VERSION 5.7 ;
  NOWIREEXTENSIONATPIN ON ;
  DIVIDERCHAR "/" ;
  BUSBITCHARS "[]" ;
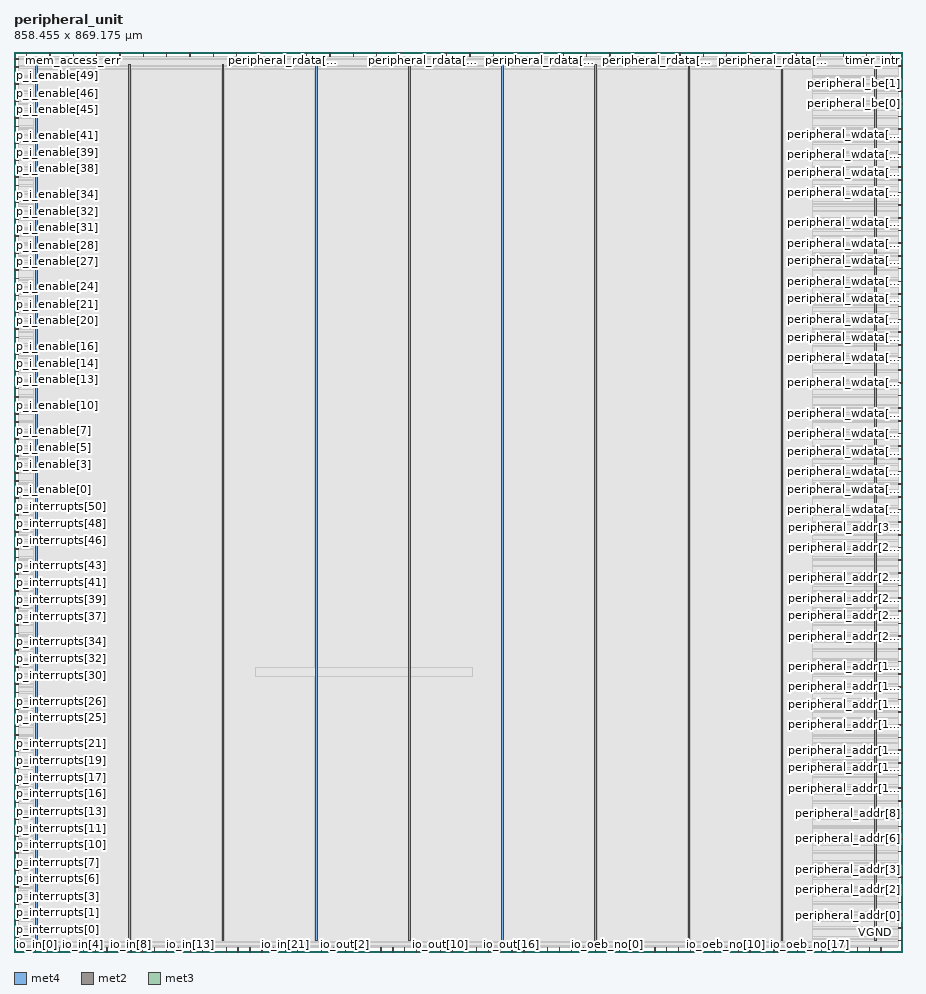
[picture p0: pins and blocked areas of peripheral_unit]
MACRO peripheral_unit
  CLASS BLOCK ;
  FOREIGN peripheral_unit ;
  ORIGIN 0.000 0.000 ;
  SIZE 858.455 BY 869.175 ;
  PIN VGND
    USE GROUND ;
    PORT
      LAYER met4 ;
        RECT 831.040 10.640 832.640 857.040 ;
    END
    PORT
      LAYER met4 ;
        RECT 651.040 10.640 652.640 857.040 ;
    END
    PORT
      LAYER met4 ;
        RECT 471.040 10.640 472.640 857.040 ;
    END
    PORT
      LAYER met4 ;
        RECT 291.040 10.640 292.640 857.040 ;
    END
    PORT
      LAYER met4 ;
        RECT 111.040 10.640 112.640 857.040 ;
    END
  END VGND
  PIN VPWR
    USE POWER ;
    PORT
      LAYER met4 ;
        RECT 741.040 10.640 742.640 857.040 ;
    END
    PORT
      LAYER met4 ;
        RECT 561.040 10.640 562.640 857.040 ;
    END
    PORT
      LAYER met4 ;
        RECT 381.040 10.640 382.640 857.040 ;
    END
    PORT
      LAYER met4 ;
        RECT 201.040 10.640 202.640 857.040 ;
    END
    PORT
      LAYER met4 ;
        RECT 21.040 10.640 22.640 857.040 ;
    END
  END VPWR
  PIN clk
    PORT
      LAYER met2 ;
        RECT 12.050 865.175 12.330 869.175 ;
    END
  END clk
  PIN io_in[0]
    PORT
      LAYER met2 ;
        RECT 20.790 0.000 21.070 4.000 ;
    END
  END io_in[0]
  PIN io_in[10]
    PORT
      LAYER met2 ;
        RECT 135.790 0.000 136.070 4.000 ;
    END
  END io_in[10]
  PIN io_in[11]
    PORT
      LAYER met2 ;
        RECT 147.290 0.000 147.570 4.000 ;
    END
  END io_in[11]
  PIN io_in[12]
    PORT
      LAYER met2 ;
        RECT 158.790 0.000 159.070 4.000 ;
    END
  END io_in[12]
  PIN io_in[13]
    PORT
      LAYER met2 ;
        RECT 170.290 0.000 170.570 4.000 ;
    END
  END io_in[13]
  PIN io_in[14]
    PORT
      LAYER met2 ;
        RECT 181.790 0.000 182.070 4.000 ;
    END
  END io_in[14]
  PIN io_in[15]
    PORT
      LAYER met2 ;
        RECT 193.290 0.000 193.570 4.000 ;
    END
  END io_in[15]
  PIN io_in[16]
    PORT
      LAYER met2 ;
        RECT 204.790 0.000 205.070 4.000 ;
    END
  END io_in[16]
  PIN io_in[17]
    PORT
      LAYER met2 ;
        RECT 216.290 0.000 216.570 4.000 ;
    END
  END io_in[17]
  PIN io_in[18]
    PORT
      LAYER met2 ;
        RECT 227.790 0.000 228.070 4.000 ;
    END
  END io_in[18]
  PIN io_in[19]
    PORT
      LAYER met2 ;
        RECT 239.290 0.000 239.570 4.000 ;
    END
  END io_in[19]
  PIN io_in[1]
    PORT
      LAYER met2 ;
        RECT 32.290 0.000 32.570 4.000 ;
    END
  END io_in[1]
  PIN io_in[20]
    PORT
      LAYER met2 ;
        RECT 250.790 0.000 251.070 4.000 ;
    END
  END io_in[20]
  PIN io_in[21]
    PORT
      LAYER met2 ;
        RECT 262.290 0.000 262.570 4.000 ;
    END
  END io_in[21]
  PIN io_in[22]
    PORT
      LAYER met2 ;
        RECT 273.790 0.000 274.070 4.000 ;
    END
  END io_in[22]
  PIN io_in[23]
    PORT
      LAYER met2 ;
        RECT 285.290 0.000 285.570 4.000 ;
    END
  END io_in[23]
  PIN io_in[2]
    PORT
      LAYER met2 ;
        RECT 43.790 0.000 44.070 4.000 ;
    END
  END io_in[2]
  PIN io_in[3]
    PORT
      LAYER met2 ;
        RECT 55.290 0.000 55.570 4.000 ;
    END
  END io_in[3]
  PIN io_in[4]
    PORT
      LAYER met2 ;
        RECT 66.790 0.000 67.070 4.000 ;
    END
  END io_in[4]
  PIN io_in[5]
    PORT
      LAYER met2 ;
        RECT 78.290 0.000 78.570 4.000 ;
    END
  END io_in[5]
  PIN io_in[6]
    PORT
      LAYER met2 ;
        RECT 89.790 0.000 90.070 4.000 ;
    END
  END io_in[6]
  PIN io_in[7]
    PORT
      LAYER met2 ;
        RECT 101.290 0.000 101.570 4.000 ;
    END
  END io_in[7]
  PIN io_in[8]
    PORT
      LAYER met2 ;
        RECT 112.790 0.000 113.070 4.000 ;
    END
  END io_in[8]
  PIN io_in[9]
    PORT
      LAYER met2 ;
        RECT 124.290 0.000 124.570 4.000 ;
    END
  END io_in[9]
  PIN io_oeb_no[0]
    PORT
      LAYER met2 ;
        RECT 572.790 0.000 573.070 4.000 ;
    END
  END io_oeb_no[0]
  PIN io_oeb_no[10]
    PORT
      LAYER met2 ;
        RECT 687.790 0.000 688.070 4.000 ;
    END
  END io_oeb_no[10]
  PIN io_oeb_no[11]
    PORT
      LAYER met2 ;
        RECT 699.290 0.000 699.570 4.000 ;
    END
  END io_oeb_no[11]
  PIN io_oeb_no[12]
    PORT
      LAYER met2 ;
        RECT 710.790 0.000 711.070 4.000 ;
    END
  END io_oeb_no[12]
  PIN io_oeb_no[13]
    PORT
      LAYER met2 ;
        RECT 722.290 0.000 722.570 4.000 ;
    END
  END io_oeb_no[13]
  PIN io_oeb_no[14]
    PORT
      LAYER met2 ;
        RECT 733.790 0.000 734.070 4.000 ;
    END
  END io_oeb_no[14]
  PIN io_oeb_no[15]
    PORT
      LAYER met2 ;
        RECT 745.290 0.000 745.570 4.000 ;
    END
  END io_oeb_no[15]
  PIN io_oeb_no[16]
    PORT
      LAYER met2 ;
        RECT 756.790 0.000 757.070 4.000 ;
    END
  END io_oeb_no[16]
  PIN io_oeb_no[17]
    PORT
      LAYER met2 ;
        RECT 768.290 0.000 768.570 4.000 ;
    END
  END io_oeb_no[17]
  PIN io_oeb_no[18]
    PORT
      LAYER met2 ;
        RECT 779.790 0.000 780.070 4.000 ;
    END
  END io_oeb_no[18]
  PIN io_oeb_no[19]
    PORT
      LAYER met2 ;
        RECT 791.290 0.000 791.570 4.000 ;
    END
  END io_oeb_no[19]
  PIN io_oeb_no[1]
    PORT
      LAYER met2 ;
        RECT 584.290 0.000 584.570 4.000 ;
    END
  END io_oeb_no[1]
  PIN io_oeb_no[20]
    PORT
      LAYER met2 ;
        RECT 802.790 0.000 803.070 4.000 ;
    END
  END io_oeb_no[20]
  PIN io_oeb_no[21]
    PORT
      LAYER met2 ;
        RECT 814.290 0.000 814.570 4.000 ;
    END
  END io_oeb_no[21]
  PIN io_oeb_no[22]
    PORT
      LAYER met2 ;
        RECT 825.790 0.000 826.070 4.000 ;
    END
  END io_oeb_no[22]
  PIN io_oeb_no[23]
    PORT
      LAYER met2 ;
        RECT 837.290 0.000 837.570 4.000 ;
    END
  END io_oeb_no[23]
  PIN io_oeb_no[2]
    PORT
      LAYER met2 ;
        RECT 595.790 0.000 596.070 4.000 ;
    END
  END io_oeb_no[2]
  PIN io_oeb_no[3]
    PORT
      LAYER met2 ;
        RECT 607.290 0.000 607.570 4.000 ;
    END
  END io_oeb_no[3]
  PIN io_oeb_no[4]
    PORT
      LAYER met2 ;
        RECT 618.790 0.000 619.070 4.000 ;
    END
  END io_oeb_no[4]
  PIN io_oeb_no[5]
    PORT
      LAYER met2 ;
        RECT 630.290 0.000 630.570 4.000 ;
    END
  END io_oeb_no[5]
  PIN io_oeb_no[6]
    PORT
      LAYER met2 ;
        RECT 641.790 0.000 642.070 4.000 ;
    END
  END io_oeb_no[6]
  PIN io_oeb_no[7]
    PORT
      LAYER met2 ;
        RECT 653.290 0.000 653.570 4.000 ;
    END
  END io_oeb_no[7]
  PIN io_oeb_no[8]
    PORT
      LAYER met2 ;
        RECT 664.790 0.000 665.070 4.000 ;
    END
  END io_oeb_no[8]
  PIN io_oeb_no[9]
    PORT
      LAYER met2 ;
        RECT 676.290 0.000 676.570 4.000 ;
    END
  END io_oeb_no[9]
  PIN io_out[0]
    PORT
      LAYER met2 ;
        RECT 296.790 0.000 297.070 4.000 ;
    END
  END io_out[0]
  PIN io_out[10]
    PORT
      LAYER met2 ;
        RECT 411.790 0.000 412.070 4.000 ;
    END
  END io_out[10]
  PIN io_out[11]
    PORT
      LAYER met2 ;
        RECT 423.290 0.000 423.570 4.000 ;
    END
  END io_out[11]
  PIN io_out[12]
    PORT
      LAYER met2 ;
        RECT 434.790 0.000 435.070 4.000 ;
    END
  END io_out[12]
  PIN io_out[13]
    PORT
      LAYER met2 ;
        RECT 446.290 0.000 446.570 4.000 ;
    END
  END io_out[13]
  PIN io_out[14]
    PORT
      LAYER met2 ;
        RECT 457.790 0.000 458.070 4.000 ;
    END
  END io_out[14]
  PIN io_out[15]
    PORT
      LAYER met2 ;
        RECT 469.290 0.000 469.570 4.000 ;
    END
  END io_out[15]
  PIN io_out[16]
    PORT
      LAYER met2 ;
        RECT 480.790 0.000 481.070 4.000 ;
    END
  END io_out[16]
  PIN io_out[17]
    PORT
      LAYER met2 ;
        RECT 492.290 0.000 492.570 4.000 ;
    END
  END io_out[17]
  PIN io_out[18]
    PORT
      LAYER met2 ;
        RECT 503.790 0.000 504.070 4.000 ;
    END
  END io_out[18]
  PIN io_out[19]
    PORT
      LAYER met2 ;
        RECT 515.290 0.000 515.570 4.000 ;
    END
  END io_out[19]
  PIN io_out[1]
    PORT
      LAYER met2 ;
        RECT 308.290 0.000 308.570 4.000 ;
    END
  END io_out[1]
  PIN io_out[20]
    PORT
      LAYER met2 ;
        RECT 526.790 0.000 527.070 4.000 ;
    END
  END io_out[20]
  PIN io_out[21]
    PORT
      LAYER met2 ;
        RECT 538.290 0.000 538.570 4.000 ;
    END
  END io_out[21]
  PIN io_out[22]
    PORT
      LAYER met2 ;
        RECT 549.790 0.000 550.070 4.000 ;
    END
  END io_out[22]
  PIN io_out[23]
    PORT
      LAYER met2 ;
        RECT 561.290 0.000 561.570 4.000 ;
    END
  END io_out[23]
  PIN io_out[2]
    PORT
      LAYER met2 ;
        RECT 319.790 0.000 320.070 4.000 ;
    END
  END io_out[2]
  PIN io_out[3]
    PORT
      LAYER met2 ;
        RECT 331.290 0.000 331.570 4.000 ;
    END
  END io_out[3]
  PIN io_out[4]
    PORT
      LAYER met2 ;
        RECT 342.790 0.000 343.070 4.000 ;
    END
  END io_out[4]
  PIN io_out[5]
    PORT
      LAYER met2 ;
        RECT 354.290 0.000 354.570 4.000 ;
    END
  END io_out[5]
  PIN io_out[6]
    PORT
      LAYER met2 ;
        RECT 365.790 0.000 366.070 4.000 ;
    END
  END io_out[6]
  PIN io_out[7]
    PORT
      LAYER met2 ;
        RECT 377.290 0.000 377.570 4.000 ;
    END
  END io_out[7]
  PIN io_out[8]
    PORT
      LAYER met2 ;
        RECT 388.790 0.000 389.070 4.000 ;
    END
  END io_out[8]
  PIN io_out[9]
    PORT
      LAYER met2 ;
        RECT 400.290 0.000 400.570 4.000 ;
    END
  END io_out[9]
  PIN me_i_en
    PORT
      LAYER met3 ;
        RECT 0.000 13.640 4.000 14.240 ;
    END
  END me_i_en
  PIN mem_access_err
    PORT
      LAYER met2 ;
        RECT 57.130 865.175 57.410 869.175 ;
    END
  END mem_access_err
  PIN mem_err_int
    PORT
      LAYER met3 ;
        RECT 0.000 5.480 4.000 6.080 ;
    END
  END mem_err_int
  PIN p_i_enable[0]
    PORT
      LAYER met3 ;
        RECT 0.000 446.120 4.000 446.720 ;
    END
  END p_i_enable[0]
  PIN p_i_enable[10]
    PORT
      LAYER met3 ;
        RECT 0.000 527.720 4.000 528.320 ;
    END
  END p_i_enable[10]
  PIN p_i_enable[11]
    PORT
      LAYER met3 ;
        RECT 0.000 535.880 4.000 536.480 ;
    END
  END p_i_enable[11]
  PIN p_i_enable[12]
    PORT
      LAYER met3 ;
        RECT 0.000 544.040 4.000 544.640 ;
    END
  END p_i_enable[12]
  PIN p_i_enable[13]
    PORT
      LAYER met3 ;
        RECT 0.000 552.200 4.000 552.800 ;
    END
  END p_i_enable[13]
  PIN p_i_enable[14]
    PORT
      LAYER met3 ;
        RECT 0.000 560.360 4.000 560.960 ;
    END
  END p_i_enable[14]
  PIN p_i_enable[15]
    PORT
      LAYER met3 ;
        RECT 0.000 568.520 4.000 569.120 ;
    END
  END p_i_enable[15]
  PIN p_i_enable[16]
    PORT
      LAYER met3 ;
        RECT 0.000 576.680 4.000 577.280 ;
    END
  END p_i_enable[16]
  PIN p_i_enable[17]
    PORT
      LAYER met3 ;
        RECT 0.000 584.840 4.000 585.440 ;
    END
  END p_i_enable[17]
  PIN p_i_enable[18]
    PORT
      LAYER met3 ;
        RECT 0.000 593.000 4.000 593.600 ;
    END
  END p_i_enable[18]
  PIN p_i_enable[19]
    PORT
      LAYER met3 ;
        RECT 0.000 601.160 4.000 601.760 ;
    END
  END p_i_enable[19]
  PIN p_i_enable[1]
    PORT
      LAYER met3 ;
        RECT 0.000 454.280 4.000 454.880 ;
    END
  END p_i_enable[1]
  PIN p_i_enable[20]
    PORT
      LAYER met3 ;
        RECT 0.000 609.320 4.000 609.920 ;
    END
  END p_i_enable[20]
  PIN p_i_enable[21]
    PORT
      LAYER met3 ;
        RECT 0.000 617.480 4.000 618.080 ;
    END
  END p_i_enable[21]
  PIN p_i_enable[22]
    PORT
      LAYER met3 ;
        RECT 0.000 625.640 4.000 626.240 ;
    END
  END p_i_enable[22]
  PIN p_i_enable[23]
    PORT
      LAYER met3 ;
        RECT 0.000 633.800 4.000 634.400 ;
    END
  END p_i_enable[23]
  PIN p_i_enable[24]
    PORT
      LAYER met3 ;
        RECT 0.000 641.960 4.000 642.560 ;
    END
  END p_i_enable[24]
  PIN p_i_enable[25]
    PORT
      LAYER met3 ;
        RECT 0.000 650.120 4.000 650.720 ;
    END
  END p_i_enable[25]
  PIN p_i_enable[26]
    PORT
      LAYER met3 ;
        RECT 0.000 658.280 4.000 658.880 ;
    END
  END p_i_enable[26]
  PIN p_i_enable[27]
    PORT
      LAYER met3 ;
        RECT 0.000 666.440 4.000 667.040 ;
    END
  END p_i_enable[27]
  PIN p_i_enable[28]
    PORT
      LAYER met3 ;
        RECT 0.000 674.600 4.000 675.200 ;
    END
  END p_i_enable[28]
  PIN p_i_enable[29]
    PORT
      LAYER met3 ;
        RECT 0.000 682.760 4.000 683.360 ;
    END
  END p_i_enable[29]
  PIN p_i_enable[2]
    PORT
      LAYER met3 ;
        RECT 0.000 462.440 4.000 463.040 ;
    END
  END p_i_enable[2]
  PIN p_i_enable[30]
    PORT
      LAYER met3 ;
        RECT 0.000 690.920 4.000 691.520 ;
    END
  END p_i_enable[30]
  PIN p_i_enable[31]
    PORT
      LAYER met3 ;
        RECT 0.000 699.080 4.000 699.680 ;
    END
  END p_i_enable[31]
  PIN p_i_enable[32]
    PORT
      LAYER met3 ;
        RECT 0.000 707.240 4.000 707.840 ;
    END
  END p_i_enable[32]
  PIN p_i_enable[33]
    PORT
      LAYER met3 ;
        RECT 0.000 715.400 4.000 716.000 ;
    END
  END p_i_enable[33]
  PIN p_i_enable[34]
    PORT
      LAYER met3 ;
        RECT 0.000 723.560 4.000 724.160 ;
    END
  END p_i_enable[34]
  PIN p_i_enable[35]
    PORT
      LAYER met3 ;
        RECT 0.000 731.720 4.000 732.320 ;
    END
  END p_i_enable[35]
  PIN p_i_enable[36]
    PORT
      LAYER met3 ;
        RECT 0.000 739.880 4.000 740.480 ;
    END
  END p_i_enable[36]
  PIN p_i_enable[37]
    PORT
      LAYER met3 ;
        RECT 0.000 748.040 4.000 748.640 ;
    END
  END p_i_enable[37]
  PIN p_i_enable[38]
    PORT
      LAYER met3 ;
        RECT 0.000 756.200 4.000 756.800 ;
    END
  END p_i_enable[38]
  PIN p_i_enable[39]
    PORT
      LAYER met3 ;
        RECT 0.000 764.360 4.000 764.960 ;
    END
  END p_i_enable[39]
  PIN p_i_enable[3]
    PORT
      LAYER met3 ;
        RECT 0.000 470.600 4.000 471.200 ;
    END
  END p_i_enable[3]
  PIN p_i_enable[40]
    PORT
      LAYER met3 ;
        RECT 0.000 772.520 4.000 773.120 ;
    END
  END p_i_enable[40]
  PIN p_i_enable[41]
    PORT
      LAYER met3 ;
        RECT 0.000 780.680 4.000 781.280 ;
    END
  END p_i_enable[41]
  PIN p_i_enable[42]
    PORT
      LAYER met3 ;
        RECT 0.000 788.840 4.000 789.440 ;
    END
  END p_i_enable[42]
  PIN p_i_enable[43]
    PORT
      LAYER met3 ;
        RECT 0.000 797.000 4.000 797.600 ;
    END
  END p_i_enable[43]
  PIN p_i_enable[44]
    PORT
      LAYER met3 ;
        RECT 0.000 805.160 4.000 805.760 ;
    END
  END p_i_enable[44]
  PIN p_i_enable[45]
    PORT
      LAYER met3 ;
        RECT 0.000 813.320 4.000 813.920 ;
    END
  END p_i_enable[45]
  PIN p_i_enable[46]
    PORT
      LAYER met3 ;
        RECT 0.000 821.480 4.000 822.080 ;
    END
  END p_i_enable[46]
  PIN p_i_enable[47]
    PORT
      LAYER met3 ;
        RECT 0.000 829.640 4.000 830.240 ;
    END
  END p_i_enable[47]
  PIN p_i_enable[48]
    PORT
      LAYER met3 ;
        RECT 0.000 837.800 4.000 838.400 ;
    END
  END p_i_enable[48]
  PIN p_i_enable[49]
    PORT
      LAYER met3 ;
        RECT 0.000 845.960 4.000 846.560 ;
    END
  END p_i_enable[49]
  PIN p_i_enable[4]
    PORT
      LAYER met3 ;
        RECT 0.000 478.760 4.000 479.360 ;
    END
  END p_i_enable[4]
  PIN p_i_enable[50]
    PORT
      LAYER met3 ;
        RECT 0.000 854.120 4.000 854.720 ;
    END
  END p_i_enable[50]
  PIN p_i_enable[51]
    PORT
      LAYER met3 ;
        RECT 0.000 862.280 4.000 862.880 ;
    END
  END p_i_enable[51]
  PIN p_i_enable[5]
    PORT
      LAYER met3 ;
        RECT 0.000 486.920 4.000 487.520 ;
    END
  END p_i_enable[5]
  PIN p_i_enable[6]
    PORT
      LAYER met3 ;
        RECT 0.000 495.080 4.000 495.680 ;
    END
  END p_i_enable[6]
  PIN p_i_enable[7]
    PORT
      LAYER met3 ;
        RECT 0.000 503.240 4.000 503.840 ;
    END
  END p_i_enable[7]
  PIN p_i_enable[8]
    PORT
      LAYER met3 ;
        RECT 0.000 511.400 4.000 512.000 ;
    END
  END p_i_enable[8]
  PIN p_i_enable[9]
    PORT
      LAYER met3 ;
        RECT 0.000 519.560 4.000 520.160 ;
    END
  END p_i_enable[9]
  PIN p_interrupts[0]
    PORT
      LAYER met3 ;
        RECT 0.000 21.800 4.000 22.400 ;
    END
  END p_interrupts[0]
  PIN p_interrupts[10]
    PORT
      LAYER met3 ;
        RECT 0.000 103.400 4.000 104.000 ;
    END
  END p_interrupts[10]
  PIN p_interrupts[11]
    PORT
      LAYER met3 ;
        RECT 0.000 111.560 4.000 112.160 ;
    END
  END p_interrupts[11]
  PIN p_interrupts[12]
    PORT
      LAYER met3 ;
        RECT 0.000 119.720 4.000 120.320 ;
    END
  END p_interrupts[12]
  PIN p_interrupts[13]
    PORT
      LAYER met3 ;
        RECT 0.000 127.880 4.000 128.480 ;
    END
  END p_interrupts[13]
  PIN p_interrupts[14]
    PORT
      LAYER met3 ;
        RECT 0.000 136.040 4.000 136.640 ;
    END
  END p_interrupts[14]
  PIN p_interrupts[15]
    PORT
      LAYER met3 ;
        RECT 0.000 144.200 4.000 144.800 ;
    END
  END p_interrupts[15]
  PIN p_interrupts[16]
    PORT
      LAYER met3 ;
        RECT 0.000 152.360 4.000 152.960 ;
    END
  END p_interrupts[16]
  PIN p_interrupts[17]
    PORT
      LAYER met3 ;
        RECT 0.000 160.520 4.000 161.120 ;
    END
  END p_interrupts[17]
  PIN p_interrupts[18]
    PORT
      LAYER met3 ;
        RECT 0.000 168.680 4.000 169.280 ;
    END
  END p_interrupts[18]
  PIN p_interrupts[19]
    PORT
      LAYER met3 ;
        RECT 0.000 176.840 4.000 177.440 ;
    END
  END p_interrupts[19]
  PIN p_interrupts[1]
    PORT
      LAYER met3 ;
        RECT 0.000 29.960 4.000 30.560 ;
    END
  END p_interrupts[1]
  PIN p_interrupts[20]
    PORT
      LAYER met3 ;
        RECT 0.000 185.000 4.000 185.600 ;
    END
  END p_interrupts[20]
  PIN p_interrupts[21]
    PORT
      LAYER met3 ;
        RECT 0.000 193.160 4.000 193.760 ;
    END
  END p_interrupts[21]
  PIN p_interrupts[22]
    PORT
      LAYER met3 ;
        RECT 0.000 201.320 4.000 201.920 ;
    END
  END p_interrupts[22]
  PIN p_interrupts[23]
    PORT
      LAYER met3 ;
        RECT 0.000 209.480 4.000 210.080 ;
    END
  END p_interrupts[23]
  PIN p_interrupts[24]
    PORT
      LAYER met3 ;
        RECT 0.000 217.640 4.000 218.240 ;
    END
  END p_interrupts[24]
  PIN p_interrupts[25]
    PORT
      LAYER met3 ;
        RECT 0.000 225.800 4.000 226.400 ;
    END
  END p_interrupts[25]
  PIN p_interrupts[26]
    PORT
      LAYER met3 ;
        RECT 0.000 233.960 4.000 234.560 ;
    END
  END p_interrupts[26]
  PIN p_interrupts[27]
    PORT
      LAYER met3 ;
        RECT 0.000 242.120 4.000 242.720 ;
    END
  END p_interrupts[27]
  PIN p_interrupts[28]
    PORT
      LAYER met3 ;
        RECT 0.000 250.280 4.000 250.880 ;
    END
  END p_interrupts[28]
  PIN p_interrupts[29]
    PORT
      LAYER met3 ;
        RECT 0.000 258.440 4.000 259.040 ;
    END
  END p_interrupts[29]
  PIN p_interrupts[2]
    PORT
      LAYER met3 ;
        RECT 0.000 38.120 4.000 38.720 ;
    END
  END p_interrupts[2]
  PIN p_interrupts[30]
    PORT
      LAYER met3 ;
        RECT 0.000 266.600 4.000 267.200 ;
    END
  END p_interrupts[30]
  PIN p_interrupts[31]
    PORT
      LAYER met3 ;
        RECT 0.000 274.760 4.000 275.360 ;
    END
  END p_interrupts[31]
  PIN p_interrupts[32]
    PORT
      LAYER met3 ;
        RECT 0.000 282.920 4.000 283.520 ;
    END
  END p_interrupts[32]
  PIN p_interrupts[33]
    PORT
      LAYER met3 ;
        RECT 0.000 291.080 4.000 291.680 ;
    END
  END p_interrupts[33]
  PIN p_interrupts[34]
    PORT
      LAYER met3 ;
        RECT 0.000 299.240 4.000 299.840 ;
    END
  END p_interrupts[34]
  PIN p_interrupts[35]
    PORT
      LAYER met3 ;
        RECT 0.000 307.400 4.000 308.000 ;
    END
  END p_interrupts[35]
  PIN p_interrupts[36]
    PORT
      LAYER met3 ;
        RECT 0.000 315.560 4.000 316.160 ;
    END
  END p_interrupts[36]
  PIN p_interrupts[37]
    PORT
      LAYER met3 ;
        RECT 0.000 323.720 4.000 324.320 ;
    END
  END p_interrupts[37]
  PIN p_interrupts[38]
    PORT
      LAYER met3 ;
        RECT 0.000 331.880 4.000 332.480 ;
    END
  END p_interrupts[38]
  PIN p_interrupts[39]
    PORT
      LAYER met3 ;
        RECT 0.000 340.040 4.000 340.640 ;
    END
  END p_interrupts[39]
  PIN p_interrupts[3]
    PORT
      LAYER met3 ;
        RECT 0.000 46.280 4.000 46.880 ;
    END
  END p_interrupts[3]
  PIN p_interrupts[40]
    PORT
      LAYER met3 ;
        RECT 0.000 348.200 4.000 348.800 ;
    END
  END p_interrupts[40]
  PIN p_interrupts[41]
    PORT
      LAYER met3 ;
        RECT 0.000 356.360 4.000 356.960 ;
    END
  END p_interrupts[41]
  PIN p_interrupts[42]
    PORT
      LAYER met3 ;
        RECT 0.000 364.520 4.000 365.120 ;
    END
  END p_interrupts[42]
  PIN p_interrupts[43]
    PORT
      LAYER met3 ;
        RECT 0.000 372.680 4.000 373.280 ;
    END
  END p_interrupts[43]
  PIN p_interrupts[44]
    PORT
      LAYER met3 ;
        RECT 0.000 380.840 4.000 381.440 ;
    END
  END p_interrupts[44]
  PIN p_interrupts[45]
    PORT
      LAYER met3 ;
        RECT 0.000 389.000 4.000 389.600 ;
    END
  END p_interrupts[45]
  PIN p_interrupts[46]
    PORT
      LAYER met3 ;
        RECT 0.000 397.160 4.000 397.760 ;
    END
  END p_interrupts[46]
  PIN p_interrupts[47]
    PORT
      LAYER met3 ;
        RECT 0.000 405.320 4.000 405.920 ;
    END
  END p_interrupts[47]
  PIN p_interrupts[48]
    PORT
      LAYER met3 ;
        RECT 0.000 413.480 4.000 414.080 ;
    END
  END p_interrupts[48]
  PIN p_interrupts[49]
    PORT
      LAYER met3 ;
        RECT 0.000 421.640 4.000 422.240 ;
    END
  END p_interrupts[49]
  PIN p_interrupts[4]
    PORT
      LAYER met3 ;
        RECT 0.000 54.440 4.000 55.040 ;
    END
  END p_interrupts[4]
  PIN p_interrupts[50]
    PORT
      LAYER met3 ;
        RECT 0.000 429.800 4.000 430.400 ;
    END
  END p_interrupts[50]
  PIN p_interrupts[51]
    PORT
      LAYER met3 ;
        RECT 0.000 437.960 4.000 438.560 ;
    END
  END p_interrupts[51]
  PIN p_interrupts[5]
    PORT
      LAYER met3 ;
        RECT 0.000 62.600 4.000 63.200 ;
    END
  END p_interrupts[5]
  PIN p_interrupts[6]
    PORT
      LAYER met3 ;
        RECT 0.000 70.760 4.000 71.360 ;
    END
  END p_interrupts[6]
  PIN p_interrupts[7]
    PORT
      LAYER met3 ;
        RECT 0.000 78.920 4.000 79.520 ;
    END
  END p_interrupts[7]
  PIN p_interrupts[8]
    PORT
      LAYER met3 ;
        RECT 0.000 87.080 4.000 87.680 ;
    END
  END p_interrupts[8]
  PIN p_interrupts[9]
    PORT
      LAYER met3 ;
        RECT 0.000 95.240 4.000 95.840 ;
    END
  END p_interrupts[9]
  PIN peripheral_addr[0]
    PORT
      LAYER met3 ;
        RECT 854.455 35.400 858.455 36.000 ;
    END
  END peripheral_addr[0]
  PIN peripheral_addr[10]
    PORT
      LAYER met3 ;
        RECT 854.455 157.800 858.455 158.400 ;
    END
  END peripheral_addr[10]
  PIN peripheral_addr[11]
    PORT
      LAYER met3 ;
        RECT 854.455 170.040 858.455 170.640 ;
    END
  END peripheral_addr[11]
  PIN peripheral_addr[12]
    PORT
      LAYER met3 ;
        RECT 854.455 182.280 858.455 182.880 ;
    END
  END peripheral_addr[12]
  PIN peripheral_addr[13]
    PORT
      LAYER met3 ;
        RECT 854.455 194.520 858.455 195.120 ;
    END
  END peripheral_addr[13]
  PIN peripheral_addr[14]
    PORT
      LAYER met3 ;
        RECT 854.455 206.760 858.455 207.360 ;
    END
  END peripheral_addr[14]
  PIN peripheral_addr[15]
    PORT
      LAYER met3 ;
        RECT 854.455 219.000 858.455 219.600 ;
    END
  END peripheral_addr[15]
  PIN peripheral_addr[16]
    PORT
      LAYER met3 ;
        RECT 854.455 231.240 858.455 231.840 ;
    END
  END peripheral_addr[16]
  PIN peripheral_addr[17]
    PORT
      LAYER met3 ;
        RECT 854.455 243.480 858.455 244.080 ;
    END
  END peripheral_addr[17]
  PIN peripheral_addr[18]
    PORT
      LAYER met3 ;
        RECT 854.455 255.720 858.455 256.320 ;
    END
  END peripheral_addr[18]
  PIN peripheral_addr[19]
    PORT
      LAYER met3 ;
        RECT 854.455 267.960 858.455 268.560 ;
    END
  END peripheral_addr[19]
  PIN peripheral_addr[1]
    PORT
      LAYER met3 ;
        RECT 854.455 47.640 858.455 48.240 ;
    END
  END peripheral_addr[1]
  PIN peripheral_addr[20]
    PORT
      LAYER met3 ;
        RECT 854.455 280.200 858.455 280.800 ;
    END
  END peripheral_addr[20]
  PIN peripheral_addr[21]
    PORT
      LAYER met3 ;
        RECT 854.455 292.440 858.455 293.040 ;
    END
  END peripheral_addr[21]
  PIN peripheral_addr[22]
    PORT
      LAYER met3 ;
        RECT 854.455 304.680 858.455 305.280 ;
    END
  END peripheral_addr[22]
  PIN peripheral_addr[23]
    PORT
      LAYER met3 ;
        RECT 854.455 316.920 858.455 317.520 ;
    END
  END peripheral_addr[23]
  PIN peripheral_addr[24]
    PORT
      LAYER met3 ;
        RECT 854.455 329.160 858.455 329.760 ;
    END
  END peripheral_addr[24]
  PIN peripheral_addr[25]
    PORT
      LAYER met3 ;
        RECT 854.455 341.400 858.455 342.000 ;
    END
  END peripheral_addr[25]
  PIN peripheral_addr[26]
    PORT
      LAYER met3 ;
        RECT 854.455 353.640 858.455 354.240 ;
    END
  END peripheral_addr[26]
  PIN peripheral_addr[27]
    PORT
      LAYER met3 ;
        RECT 854.455 365.880 858.455 366.480 ;
    END
  END peripheral_addr[27]
  PIN peripheral_addr[28]
    PORT
      LAYER met3 ;
        RECT 854.455 378.120 858.455 378.720 ;
    END
  END peripheral_addr[28]
  PIN peripheral_addr[29]
    PORT
      LAYER met3 ;
        RECT 854.455 390.360 858.455 390.960 ;
    END
  END peripheral_addr[29]
  PIN peripheral_addr[2]
    PORT
      LAYER met3 ;
        RECT 854.455 59.880 858.455 60.480 ;
    END
  END peripheral_addr[2]
  PIN peripheral_addr[30]
    PORT
      LAYER met3 ;
        RECT 854.455 402.600 858.455 403.200 ;
    END
  END peripheral_addr[30]
  PIN peripheral_addr[31]
    PORT
      LAYER met3 ;
        RECT 854.455 414.840 858.455 415.440 ;
    END
  END peripheral_addr[31]
  PIN peripheral_addr[3]
    PORT
      LAYER met3 ;
        RECT 854.455 72.120 858.455 72.720 ;
    END
  END peripheral_addr[3]
  PIN peripheral_addr[4]
    PORT
      LAYER met3 ;
        RECT 854.455 84.360 858.455 84.960 ;
    END
  END peripheral_addr[4]
  PIN peripheral_addr[5]
    PORT
      LAYER met3 ;
        RECT 854.455 96.600 858.455 97.200 ;
    END
  END peripheral_addr[5]
  PIN peripheral_addr[6]
    PORT
      LAYER met3 ;
        RECT 854.455 108.840 858.455 109.440 ;
    END
  END peripheral_addr[6]
  PIN peripheral_addr[7]
    PORT
      LAYER met3 ;
        RECT 854.455 121.080 858.455 121.680 ;
    END
  END peripheral_addr[7]
  PIN peripheral_addr[8]
    PORT
      LAYER met3 ;
        RECT 854.455 133.320 858.455 133.920 ;
    END
  END peripheral_addr[8]
  PIN peripheral_addr[9]
    PORT
      LAYER met3 ;
        RECT 854.455 145.560 858.455 146.160 ;
    END
  END peripheral_addr[9]
  PIN peripheral_be[0]
    PORT
      LAYER met3 ;
        RECT 854.455 818.760 858.455 819.360 ;
    END
  END peripheral_be[0]
  PIN peripheral_be[1]
    PORT
      LAYER met3 ;
        RECT 854.455 831.000 858.455 831.600 ;
    END
  END peripheral_be[1]
  PIN peripheral_be[2]
    PORT
      LAYER met3 ;
        RECT 854.455 843.240 858.455 843.840 ;
    END
  END peripheral_be[2]
  PIN peripheral_be[3]
    PORT
      LAYER met3 ;
        RECT 854.455 855.480 858.455 856.080 ;
    END
  END peripheral_be[3]
  PIN peripheral_gnt
    PORT
      LAYER met2 ;
        RECT 79.670 865.175 79.950 869.175 ;
    END
  END peripheral_gnt
  PIN peripheral_rdata[0]
    PORT
      LAYER met2 ;
        RECT 124.750 865.175 125.030 869.175 ;
    END
  END peripheral_rdata[0]
  PIN peripheral_rdata[10]
    PORT
      LAYER met2 ;
        RECT 350.150 865.175 350.430 869.175 ;
    END
  END peripheral_rdata[10]
  PIN peripheral_rdata[11]
    PORT
      LAYER met2 ;
        RECT 372.690 865.175 372.970 869.175 ;
    END
  END peripheral_rdata[11]
  PIN peripheral_rdata[12]
    PORT
      LAYER met2 ;
        RECT 395.230 865.175 395.510 869.175 ;
    END
  END peripheral_rdata[12]
  PIN peripheral_rdata[13]
    PORT
      LAYER met2 ;
        RECT 417.770 865.175 418.050 869.175 ;
    END
  END peripheral_rdata[13]
  PIN peripheral_rdata[14]
    PORT
      LAYER met2 ;
        RECT 440.310 865.175 440.590 869.175 ;
    END
  END peripheral_rdata[14]
  PIN peripheral_rdata[15]
    PORT
      LAYER met2 ;
        RECT 462.850 865.175 463.130 869.175 ;
    END
  END peripheral_rdata[15]
  PIN peripheral_rdata[16]
    PORT
      LAYER met2 ;
        RECT 485.390 865.175 485.670 869.175 ;
    END
  END peripheral_rdata[16]
  PIN peripheral_rdata[17]
    PORT
      LAYER met2 ;
        RECT 507.930 865.175 508.210 869.175 ;
    END
  END peripheral_rdata[17]
  PIN peripheral_rdata[18]
    PORT
      LAYER met2 ;
        RECT 530.470 865.175 530.750 869.175 ;
    END
  END peripheral_rdata[18]
  PIN peripheral_rdata[19]
    PORT
      LAYER met2 ;
        RECT 553.010 865.175 553.290 869.175 ;
    END
  END peripheral_rdata[19]
  PIN peripheral_rdata[1]
    PORT
      LAYER met2 ;
        RECT 147.290 865.175 147.570 869.175 ;
    END
  END peripheral_rdata[1]
  PIN peripheral_rdata[20]
    PORT
      LAYER met2 ;
        RECT 575.550 865.175 575.830 869.175 ;
    END
  END peripheral_rdata[20]
  PIN peripheral_rdata[21]
    PORT
      LAYER met2 ;
        RECT 598.090 865.175 598.370 869.175 ;
    END
  END peripheral_rdata[21]
  PIN peripheral_rdata[22]
    PORT
      LAYER met2 ;
        RECT 620.630 865.175 620.910 869.175 ;
    END
  END peripheral_rdata[22]
  PIN peripheral_rdata[23]
    PORT
      LAYER met2 ;
        RECT 643.170 865.175 643.450 869.175 ;
    END
  END peripheral_rdata[23]
  PIN peripheral_rdata[24]
    PORT
      LAYER met2 ;
        RECT 665.710 865.175 665.990 869.175 ;
    END
  END peripheral_rdata[24]
  PIN peripheral_rdata[25]
    PORT
      LAYER met2 ;
        RECT 688.250 865.175 688.530 869.175 ;
    END
  END peripheral_rdata[25]
  PIN peripheral_rdata[26]
    PORT
      LAYER met2 ;
        RECT 710.790 865.175 711.070 869.175 ;
    END
  END peripheral_rdata[26]
  PIN peripheral_rdata[27]
    PORT
      LAYER met2 ;
        RECT 733.330 865.175 733.610 869.175 ;
    END
  END peripheral_rdata[27]
  PIN peripheral_rdata[28]
    PORT
      LAYER met2 ;
        RECT 755.870 865.175 756.150 869.175 ;
    END
  END peripheral_rdata[28]
  PIN peripheral_rdata[29]
    PORT
      LAYER met2 ;
        RECT 778.410 865.175 778.690 869.175 ;
    END
  END peripheral_rdata[29]
  PIN peripheral_rdata[2]
    PORT
      LAYER met2 ;
        RECT 169.830 865.175 170.110 869.175 ;
    END
  END peripheral_rdata[2]
  PIN peripheral_rdata[30]
    PORT
      LAYER met2 ;
        RECT 800.950 865.175 801.230 869.175 ;
    END
  END peripheral_rdata[30]
  PIN peripheral_rdata[31]
    PORT
      LAYER met2 ;
        RECT 823.490 865.175 823.770 869.175 ;
    END
  END peripheral_rdata[31]
  PIN peripheral_rdata[3]
    PORT
      LAYER met2 ;
        RECT 192.370 865.175 192.650 869.175 ;
    END
  END peripheral_rdata[3]
  PIN peripheral_rdata[4]
    PORT
      LAYER met2 ;
        RECT 214.910 865.175 215.190 869.175 ;
    END
  END peripheral_rdata[4]
  PIN peripheral_rdata[5]
    PORT
      LAYER met2 ;
        RECT 237.450 865.175 237.730 869.175 ;
    END
  END peripheral_rdata[5]
  PIN peripheral_rdata[6]
    PORT
      LAYER met2 ;
        RECT 259.990 865.175 260.270 869.175 ;
    END
  END peripheral_rdata[6]
  PIN peripheral_rdata[7]
    PORT
      LAYER met2 ;
        RECT 282.530 865.175 282.810 869.175 ;
    END
  END peripheral_rdata[7]
  PIN peripheral_rdata[8]
    PORT
      LAYER met2 ;
        RECT 305.070 865.175 305.350 869.175 ;
    END
  END peripheral_rdata[8]
  PIN peripheral_rdata[9]
    PORT
      LAYER met2 ;
        RECT 327.610 865.175 327.890 869.175 ;
    END
  END peripheral_rdata[9]
  PIN peripheral_req
    PORT
      LAYER met3 ;
        RECT 854.455 10.920 858.455 11.520 ;
    END
  END peripheral_req
  PIN peripheral_rvalid
    PORT
      LAYER met2 ;
        RECT 102.210 865.175 102.490 869.175 ;
    END
  END peripheral_rvalid
  PIN peripheral_wdata[0]
    PORT
      LAYER met3 ;
        RECT 854.455 427.080 858.455 427.680 ;
    END
  END peripheral_wdata[0]
  PIN peripheral_wdata[10]
    PORT
      LAYER met3 ;
        RECT 854.455 549.480 858.455 550.080 ;
    END
  END peripheral_wdata[10]
  PIN peripheral_wdata[11]
    PORT
      LAYER met3 ;
        RECT 854.455 561.720 858.455 562.320 ;
    END
  END peripheral_wdata[11]
  PIN peripheral_wdata[12]
    PORT
      LAYER met3 ;
        RECT 854.455 573.960 858.455 574.560 ;
    END
  END peripheral_wdata[12]
  PIN peripheral_wdata[13]
    PORT
      LAYER met3 ;
        RECT 854.455 586.200 858.455 586.800 ;
    END
  END peripheral_wdata[13]
  PIN peripheral_wdata[14]
    PORT
      LAYER met3 ;
        RECT 854.455 598.440 858.455 599.040 ;
    END
  END peripheral_wdata[14]
  PIN peripheral_wdata[15]
    PORT
      LAYER met3 ;
        RECT 854.455 610.680 858.455 611.280 ;
    END
  END peripheral_wdata[15]
  PIN peripheral_wdata[16]
    PORT
      LAYER met3 ;
        RECT 854.455 622.920 858.455 623.520 ;
    END
  END peripheral_wdata[16]
  PIN peripheral_wdata[17]
    PORT
      LAYER met3 ;
        RECT 854.455 635.160 858.455 635.760 ;
    END
  END peripheral_wdata[17]
  PIN peripheral_wdata[18]
    PORT
      LAYER met3 ;
        RECT 854.455 647.400 858.455 648.000 ;
    END
  END peripheral_wdata[18]
  PIN peripheral_wdata[19]
    PORT
      LAYER met3 ;
        RECT 854.455 659.640 858.455 660.240 ;
    END
  END peripheral_wdata[19]
  PIN peripheral_wdata[1]
    PORT
      LAYER met3 ;
        RECT 854.455 439.320 858.455 439.920 ;
    END
  END peripheral_wdata[1]
  PIN peripheral_wdata[20]
    PORT
      LAYER met3 ;
        RECT 854.455 671.880 858.455 672.480 ;
    END
  END peripheral_wdata[20]
  PIN peripheral_wdata[21]
    PORT
      LAYER met3 ;
        RECT 854.455 684.120 858.455 684.720 ;
    END
  END peripheral_wdata[21]
  PIN peripheral_wdata[22]
    PORT
      LAYER met3 ;
        RECT 854.455 696.360 858.455 696.960 ;
    END
  END peripheral_wdata[22]
  PIN peripheral_wdata[23]
    PORT
      LAYER met3 ;
        RECT 854.455 708.600 858.455 709.200 ;
    END
  END peripheral_wdata[23]
  PIN peripheral_wdata[24]
    PORT
      LAYER met3 ;
        RECT 854.455 720.840 858.455 721.440 ;
    END
  END peripheral_wdata[24]
  PIN peripheral_wdata[25]
    PORT
      LAYER met3 ;
        RECT 854.455 733.080 858.455 733.680 ;
    END
  END peripheral_wdata[25]
  PIN peripheral_wdata[26]
    PORT
      LAYER met3 ;
        RECT 854.455 745.320 858.455 745.920 ;
    END
  END peripheral_wdata[26]
  PIN peripheral_wdata[27]
    PORT
      LAYER met3 ;
        RECT 854.455 757.560 858.455 758.160 ;
    END
  END peripheral_wdata[27]
  PIN peripheral_wdata[28]
    PORT
      LAYER met3 ;
        RECT 854.455 769.800 858.455 770.400 ;
    END
  END peripheral_wdata[28]
  PIN peripheral_wdata[29]
    PORT
      LAYER met3 ;
        RECT 854.455 782.040 858.455 782.640 ;
    END
  END peripheral_wdata[29]
  PIN peripheral_wdata[2]
    PORT
      LAYER met3 ;
        RECT 854.455 451.560 858.455 452.160 ;
    END
  END peripheral_wdata[2]
  PIN peripheral_wdata[30]
    PORT
      LAYER met3 ;
        RECT 854.455 794.280 858.455 794.880 ;
    END
  END peripheral_wdata[30]
  PIN peripheral_wdata[31]
    PORT
      LAYER met3 ;
        RECT 854.455 806.520 858.455 807.120 ;
    END
  END peripheral_wdata[31]
  PIN peripheral_wdata[3]
    PORT
      LAYER met3 ;
        RECT 854.455 463.800 858.455 464.400 ;
    END
  END peripheral_wdata[3]
  PIN peripheral_wdata[4]
    PORT
      LAYER met3 ;
        RECT 854.455 476.040 858.455 476.640 ;
    END
  END peripheral_wdata[4]
  PIN peripheral_wdata[5]
    PORT
      LAYER met3 ;
        RECT 854.455 488.280 858.455 488.880 ;
    END
  END peripheral_wdata[5]
  PIN peripheral_wdata[6]
    PORT
      LAYER met3 ;
        RECT 854.455 500.520 858.455 501.120 ;
    END
  END peripheral_wdata[6]
  PIN peripheral_wdata[7]
    PORT
      LAYER met3 ;
        RECT 854.455 512.760 858.455 513.360 ;
    END
  END peripheral_wdata[7]
  PIN peripheral_wdata[8]
    PORT
      LAYER met3 ;
        RECT 854.455 525.000 858.455 525.600 ;
    END
  END peripheral_wdata[8]
  PIN peripheral_wdata[9]
    PORT
      LAYER met3 ;
        RECT 854.455 537.240 858.455 537.840 ;
    END
  END peripheral_wdata[9]
  PIN peripheral_we
    PORT
      LAYER met3 ;
        RECT 854.455 23.160 858.455 23.760 ;
    END
  END peripheral_we
  PIN reset_n
    PORT
      LAYER met2 ;
        RECT 34.590 865.175 34.870 869.175 ;
    END
  END reset_n
  PIN timer_intr
    PORT
      LAYER met2 ;
        RECT 846.030 865.175 846.310 869.175 ;
    END
  END timer_intr
  OBS
      LAYER li1 ;
        RECT 5.520 10.795 852.840 856.885 ;
      LAYER met1 ;
        RECT 4.670 9.220 853.690 857.040 ;
      LAYER met2 ;
        RECT 4.690 864.895 11.770 865.175 ;
        RECT 12.610 864.895 34.310 865.175 ;
        RECT 35.150 864.895 56.850 865.175 ;
        RECT 57.690 864.895 79.390 865.175 ;
        RECT 80.230 864.895 101.930 865.175 ;
        RECT 102.770 864.895 124.470 865.175 ;
        RECT 125.310 864.895 147.010 865.175 ;
        RECT 147.850 864.895 169.550 865.175 ;
        RECT 170.390 864.895 192.090 865.175 ;
        RECT 192.930 864.895 214.630 865.175 ;
        RECT 215.470 864.895 237.170 865.175 ;
        RECT 238.010 864.895 259.710 865.175 ;
        RECT 260.550 864.895 282.250 865.175 ;
        RECT 283.090 864.895 304.790 865.175 ;
        RECT 305.630 864.895 327.330 865.175 ;
        RECT 328.170 864.895 349.870 865.175 ;
        RECT 350.710 864.895 372.410 865.175 ;
        RECT 373.250 864.895 394.950 865.175 ;
        RECT 395.790 864.895 417.490 865.175 ;
        RECT 418.330 864.895 440.030 865.175 ;
        RECT 440.870 864.895 462.570 865.175 ;
        RECT 463.410 864.895 485.110 865.175 ;
        RECT 485.950 864.895 507.650 865.175 ;
        RECT 508.490 864.895 530.190 865.175 ;
        RECT 531.030 864.895 552.730 865.175 ;
        RECT 553.570 864.895 575.270 865.175 ;
        RECT 576.110 864.895 597.810 865.175 ;
        RECT 598.650 864.895 620.350 865.175 ;
        RECT 621.190 864.895 642.890 865.175 ;
        RECT 643.730 864.895 665.430 865.175 ;
        RECT 666.270 864.895 687.970 865.175 ;
        RECT 688.810 864.895 710.510 865.175 ;
        RECT 711.350 864.895 733.050 865.175 ;
        RECT 733.890 864.895 755.590 865.175 ;
        RECT 756.430 864.895 778.130 865.175 ;
        RECT 778.970 864.895 800.670 865.175 ;
        RECT 801.510 864.895 823.210 865.175 ;
        RECT 824.050 864.895 845.750 865.175 ;
        RECT 846.590 864.895 853.660 865.175 ;
        RECT 4.690 4.280 853.660 864.895 ;
        RECT 4.690 4.000 20.510 4.280 ;
        RECT 21.350 4.000 32.010 4.280 ;
        RECT 32.850 4.000 43.510 4.280 ;
        RECT 44.350 4.000 55.010 4.280 ;
        RECT 55.850 4.000 66.510 4.280 ;
        RECT 67.350 4.000 78.010 4.280 ;
        RECT 78.850 4.000 89.510 4.280 ;
        RECT 90.350 4.000 101.010 4.280 ;
        RECT 101.850 4.000 112.510 4.280 ;
        RECT 113.350 4.000 124.010 4.280 ;
        RECT 124.850 4.000 135.510 4.280 ;
        RECT 136.350 4.000 147.010 4.280 ;
        RECT 147.850 4.000 158.510 4.280 ;
        RECT 159.350 4.000 170.010 4.280 ;
        RECT 170.850 4.000 181.510 4.280 ;
        RECT 182.350 4.000 193.010 4.280 ;
        RECT 193.850 4.000 204.510 4.280 ;
        RECT 205.350 4.000 216.010 4.280 ;
        RECT 216.850 4.000 227.510 4.280 ;
        RECT 228.350 4.000 239.010 4.280 ;
        RECT 239.850 4.000 250.510 4.280 ;
        RECT 251.350 4.000 262.010 4.280 ;
        RECT 262.850 4.000 273.510 4.280 ;
        RECT 274.350 4.000 285.010 4.280 ;
        RECT 285.850 4.000 296.510 4.280 ;
        RECT 297.350 4.000 308.010 4.280 ;
        RECT 308.850 4.000 319.510 4.280 ;
        RECT 320.350 4.000 331.010 4.280 ;
        RECT 331.850 4.000 342.510 4.280 ;
        RECT 343.350 4.000 354.010 4.280 ;
        RECT 354.850 4.000 365.510 4.280 ;
        RECT 366.350 4.000 377.010 4.280 ;
        RECT 377.850 4.000 388.510 4.280 ;
        RECT 389.350 4.000 400.010 4.280 ;
        RECT 400.850 4.000 411.510 4.280 ;
        RECT 412.350 4.000 423.010 4.280 ;
        RECT 423.850 4.000 434.510 4.280 ;
        RECT 435.350 4.000 446.010 4.280 ;
        RECT 446.850 4.000 457.510 4.280 ;
        RECT 458.350 4.000 469.010 4.280 ;
        RECT 469.850 4.000 480.510 4.280 ;
        RECT 481.350 4.000 492.010 4.280 ;
        RECT 492.850 4.000 503.510 4.280 ;
        RECT 504.350 4.000 515.010 4.280 ;
        RECT 515.850 4.000 526.510 4.280 ;
        RECT 527.350 4.000 538.010 4.280 ;
        RECT 538.850 4.000 549.510 4.280 ;
        RECT 550.350 4.000 561.010 4.280 ;
        RECT 561.850 4.000 572.510 4.280 ;
        RECT 573.350 4.000 584.010 4.280 ;
        RECT 584.850 4.000 595.510 4.280 ;
        RECT 596.350 4.000 607.010 4.280 ;
        RECT 607.850 4.000 618.510 4.280 ;
        RECT 619.350 4.000 630.010 4.280 ;
        RECT 630.850 4.000 641.510 4.280 ;
        RECT 642.350 4.000 653.010 4.280 ;
        RECT 653.850 4.000 664.510 4.280 ;
        RECT 665.350 4.000 676.010 4.280 ;
        RECT 676.850 4.000 687.510 4.280 ;
        RECT 688.350 4.000 699.010 4.280 ;
        RECT 699.850 4.000 710.510 4.280 ;
        RECT 711.350 4.000 722.010 4.280 ;
        RECT 722.850 4.000 733.510 4.280 ;
        RECT 734.350 4.000 745.010 4.280 ;
        RECT 745.850 4.000 756.510 4.280 ;
        RECT 757.350 4.000 768.010 4.280 ;
        RECT 768.850 4.000 779.510 4.280 ;
        RECT 780.350 4.000 791.010 4.280 ;
        RECT 791.850 4.000 802.510 4.280 ;
        RECT 803.350 4.000 814.010 4.280 ;
        RECT 814.850 4.000 825.510 4.280 ;
        RECT 826.350 4.000 837.010 4.280 ;
        RECT 837.850 4.000 853.660 4.280 ;
      LAYER met3 ;
        RECT 4.400 861.880 854.455 862.745 ;
        RECT 4.000 856.480 854.455 861.880 ;
        RECT 4.000 855.120 854.055 856.480 ;
        RECT 4.400 855.080 854.055 855.120 ;
        RECT 4.400 853.720 854.455 855.080 ;
        RECT 4.000 846.960 854.455 853.720 ;
        RECT 4.400 845.560 854.455 846.960 ;
        RECT 4.000 844.240 854.455 845.560 ;
        RECT 4.000 842.840 854.055 844.240 ;
        RECT 4.000 838.800 854.455 842.840 ;
        RECT 4.400 837.400 854.455 838.800 ;
        RECT 4.000 832.000 854.455 837.400 ;
        RECT 4.000 830.640 854.055 832.000 ;
        RECT 4.400 830.600 854.055 830.640 ;
        RECT 4.400 829.240 854.455 830.600 ;
        RECT 4.000 822.480 854.455 829.240 ;
        RECT 4.400 821.080 854.455 822.480 ;
        RECT 4.000 819.760 854.455 821.080 ;
        RECT 4.000 818.360 854.055 819.760 ;
        RECT 4.000 814.320 854.455 818.360 ;
        RECT 4.400 812.920 854.455 814.320 ;
        RECT 4.000 807.520 854.455 812.920 ;
        RECT 4.000 806.160 854.055 807.520 ;
        RECT 4.400 806.120 854.055 806.160 ;
        RECT 4.400 804.760 854.455 806.120 ;
        RECT 4.000 798.000 854.455 804.760 ;
        RECT 4.400 796.600 854.455 798.000 ;
        RECT 4.000 795.280 854.455 796.600 ;
        RECT 4.000 793.880 854.055 795.280 ;
        RECT 4.000 789.840 854.455 793.880 ;
        RECT 4.400 788.440 854.455 789.840 ;
        RECT 4.000 783.040 854.455 788.440 ;
        RECT 4.000 781.680 854.055 783.040 ;
        RECT 4.400 781.640 854.055 781.680 ;
        RECT 4.400 780.280 854.455 781.640 ;
        RECT 4.000 773.520 854.455 780.280 ;
        RECT 4.400 772.120 854.455 773.520 ;
        RECT 4.000 770.800 854.455 772.120 ;
        RECT 4.000 769.400 854.055 770.800 ;
        RECT 4.000 765.360 854.455 769.400 ;
        RECT 4.400 763.960 854.455 765.360 ;
        RECT 4.000 758.560 854.455 763.960 ;
        RECT 4.000 757.200 854.055 758.560 ;
        RECT 4.400 757.160 854.055 757.200 ;
        RECT 4.400 755.800 854.455 757.160 ;
        RECT 4.000 749.040 854.455 755.800 ;
        RECT 4.400 747.640 854.455 749.040 ;
        RECT 4.000 746.320 854.455 747.640 ;
        RECT 4.000 744.920 854.055 746.320 ;
        RECT 4.000 740.880 854.455 744.920 ;
        RECT 4.400 739.480 854.455 740.880 ;
        RECT 4.000 734.080 854.455 739.480 ;
        RECT 4.000 732.720 854.055 734.080 ;
        RECT 4.400 732.680 854.055 732.720 ;
        RECT 4.400 731.320 854.455 732.680 ;
        RECT 4.000 724.560 854.455 731.320 ;
        RECT 4.400 723.160 854.455 724.560 ;
        RECT 4.000 721.840 854.455 723.160 ;
        RECT 4.000 720.440 854.055 721.840 ;
        RECT 4.000 716.400 854.455 720.440 ;
        RECT 4.400 715.000 854.455 716.400 ;
        RECT 4.000 709.600 854.455 715.000 ;
        RECT 4.000 708.240 854.055 709.600 ;
        RECT 4.400 708.200 854.055 708.240 ;
        RECT 4.400 706.840 854.455 708.200 ;
        RECT 4.000 700.080 854.455 706.840 ;
        RECT 4.400 698.680 854.455 700.080 ;
        RECT 4.000 697.360 854.455 698.680 ;
        RECT 4.000 695.960 854.055 697.360 ;
        RECT 4.000 691.920 854.455 695.960 ;
        RECT 4.400 690.520 854.455 691.920 ;
        RECT 4.000 685.120 854.455 690.520 ;
        RECT 4.000 683.760 854.055 685.120 ;
        RECT 4.400 683.720 854.055 683.760 ;
        RECT 4.400 682.360 854.455 683.720 ;
        RECT 4.000 675.600 854.455 682.360 ;
        RECT 4.400 674.200 854.455 675.600 ;
        RECT 4.000 672.880 854.455 674.200 ;
        RECT 4.000 671.480 854.055 672.880 ;
        RECT 4.000 667.440 854.455 671.480 ;
        RECT 4.400 666.040 854.455 667.440 ;
        RECT 4.000 660.640 854.455 666.040 ;
        RECT 4.000 659.280 854.055 660.640 ;
        RECT 4.400 659.240 854.055 659.280 ;
        RECT 4.400 657.880 854.455 659.240 ;
        RECT 4.000 651.120 854.455 657.880 ;
        RECT 4.400 649.720 854.455 651.120 ;
        RECT 4.000 648.400 854.455 649.720 ;
        RECT 4.000 647.000 854.055 648.400 ;
        RECT 4.000 642.960 854.455 647.000 ;
        RECT 4.400 641.560 854.455 642.960 ;
        RECT 4.000 636.160 854.455 641.560 ;
        RECT 4.000 634.800 854.055 636.160 ;
        RECT 4.400 634.760 854.055 634.800 ;
        RECT 4.400 633.400 854.455 634.760 ;
        RECT 4.000 626.640 854.455 633.400 ;
        RECT 4.400 625.240 854.455 626.640 ;
        RECT 4.000 623.920 854.455 625.240 ;
        RECT 4.000 622.520 854.055 623.920 ;
        RECT 4.000 618.480 854.455 622.520 ;
        RECT 4.400 617.080 854.455 618.480 ;
        RECT 4.000 611.680 854.455 617.080 ;
        RECT 4.000 610.320 854.055 611.680 ;
        RECT 4.400 610.280 854.055 610.320 ;
        RECT 4.400 608.920 854.455 610.280 ;
        RECT 4.000 602.160 854.455 608.920 ;
        RECT 4.400 600.760 854.455 602.160 ;
        RECT 4.000 599.440 854.455 600.760 ;
        RECT 4.000 598.040 854.055 599.440 ;
        RECT 4.000 594.000 854.455 598.040 ;
        RECT 4.400 592.600 854.455 594.000 ;
        RECT 4.000 587.200 854.455 592.600 ;
        RECT 4.000 585.840 854.055 587.200 ;
        RECT 4.400 585.800 854.055 585.840 ;
        RECT 4.400 584.440 854.455 585.800 ;
        RECT 4.000 577.680 854.455 584.440 ;
        RECT 4.400 576.280 854.455 577.680 ;
        RECT 4.000 574.960 854.455 576.280 ;
        RECT 4.000 573.560 854.055 574.960 ;
        RECT 4.000 569.520 854.455 573.560 ;
        RECT 4.400 568.120 854.455 569.520 ;
        RECT 4.000 562.720 854.455 568.120 ;
        RECT 4.000 561.360 854.055 562.720 ;
        RECT 4.400 561.320 854.055 561.360 ;
        RECT 4.400 559.960 854.455 561.320 ;
        RECT 4.000 553.200 854.455 559.960 ;
        RECT 4.400 551.800 854.455 553.200 ;
        RECT 4.000 550.480 854.455 551.800 ;
        RECT 4.000 549.080 854.055 550.480 ;
        RECT 4.000 545.040 854.455 549.080 ;
        RECT 4.400 543.640 854.455 545.040 ;
        RECT 4.000 538.240 854.455 543.640 ;
        RECT 4.000 536.880 854.055 538.240 ;
        RECT 4.400 536.840 854.055 536.880 ;
        RECT 4.400 535.480 854.455 536.840 ;
        RECT 4.000 528.720 854.455 535.480 ;
        RECT 4.400 527.320 854.455 528.720 ;
        RECT 4.000 526.000 854.455 527.320 ;
        RECT 4.000 524.600 854.055 526.000 ;
        RECT 4.000 520.560 854.455 524.600 ;
        RECT 4.400 519.160 854.455 520.560 ;
        RECT 4.000 513.760 854.455 519.160 ;
        RECT 4.000 512.400 854.055 513.760 ;
        RECT 4.400 512.360 854.055 512.400 ;
        RECT 4.400 511.000 854.455 512.360 ;
        RECT 4.000 504.240 854.455 511.000 ;
        RECT 4.400 502.840 854.455 504.240 ;
        RECT 4.000 501.520 854.455 502.840 ;
        RECT 4.000 500.120 854.055 501.520 ;
        RECT 4.000 496.080 854.455 500.120 ;
        RECT 4.400 494.680 854.455 496.080 ;
        RECT 4.000 489.280 854.455 494.680 ;
        RECT 4.000 487.920 854.055 489.280 ;
        RECT 4.400 487.880 854.055 487.920 ;
        RECT 4.400 486.520 854.455 487.880 ;
        RECT 4.000 479.760 854.455 486.520 ;
        RECT 4.400 478.360 854.455 479.760 ;
        RECT 4.000 477.040 854.455 478.360 ;
        RECT 4.000 475.640 854.055 477.040 ;
        RECT 4.000 471.600 854.455 475.640 ;
        RECT 4.400 470.200 854.455 471.600 ;
        RECT 4.000 464.800 854.455 470.200 ;
        RECT 4.000 463.440 854.055 464.800 ;
        RECT 4.400 463.400 854.055 463.440 ;
        RECT 4.400 462.040 854.455 463.400 ;
        RECT 4.000 455.280 854.455 462.040 ;
        RECT 4.400 453.880 854.455 455.280 ;
        RECT 4.000 452.560 854.455 453.880 ;
        RECT 4.000 451.160 854.055 452.560 ;
        RECT 4.000 447.120 854.455 451.160 ;
        RECT 4.400 445.720 854.455 447.120 ;
        RECT 4.000 440.320 854.455 445.720 ;
        RECT 4.000 438.960 854.055 440.320 ;
        RECT 4.400 438.920 854.055 438.960 ;
        RECT 4.400 437.560 854.455 438.920 ;
        RECT 4.000 430.800 854.455 437.560 ;
        RECT 4.400 429.400 854.455 430.800 ;
        RECT 4.000 428.080 854.455 429.400 ;
        RECT 4.000 426.680 854.055 428.080 ;
        RECT 4.000 422.640 854.455 426.680 ;
        RECT 4.400 421.240 854.455 422.640 ;
        RECT 4.000 415.840 854.455 421.240 ;
        RECT 4.000 414.480 854.055 415.840 ;
        RECT 4.400 414.440 854.055 414.480 ;
        RECT 4.400 413.080 854.455 414.440 ;
        RECT 4.000 406.320 854.455 413.080 ;
        RECT 4.400 404.920 854.455 406.320 ;
        RECT 4.000 403.600 854.455 404.920 ;
        RECT 4.000 402.200 854.055 403.600 ;
        RECT 4.000 398.160 854.455 402.200 ;
        RECT 4.400 396.760 854.455 398.160 ;
        RECT 4.000 391.360 854.455 396.760 ;
        RECT 4.000 390.000 854.055 391.360 ;
        RECT 4.400 389.960 854.055 390.000 ;
        RECT 4.400 388.600 854.455 389.960 ;
        RECT 4.000 381.840 854.455 388.600 ;
        RECT 4.400 380.440 854.455 381.840 ;
        RECT 4.000 379.120 854.455 380.440 ;
        RECT 4.000 377.720 854.055 379.120 ;
        RECT 4.000 373.680 854.455 377.720 ;
        RECT 4.400 372.280 854.455 373.680 ;
        RECT 4.000 366.880 854.455 372.280 ;
        RECT 4.000 365.520 854.055 366.880 ;
        RECT 4.400 365.480 854.055 365.520 ;
        RECT 4.400 364.120 854.455 365.480 ;
        RECT 4.000 357.360 854.455 364.120 ;
        RECT 4.400 355.960 854.455 357.360 ;
        RECT 4.000 354.640 854.455 355.960 ;
        RECT 4.000 353.240 854.055 354.640 ;
        RECT 4.000 349.200 854.455 353.240 ;
        RECT 4.400 347.800 854.455 349.200 ;
        RECT 4.000 342.400 854.455 347.800 ;
        RECT 4.000 341.040 854.055 342.400 ;
        RECT 4.400 341.000 854.055 341.040 ;
        RECT 4.400 339.640 854.455 341.000 ;
        RECT 4.000 332.880 854.455 339.640 ;
        RECT 4.400 331.480 854.455 332.880 ;
        RECT 4.000 330.160 854.455 331.480 ;
        RECT 4.000 328.760 854.055 330.160 ;
        RECT 4.000 324.720 854.455 328.760 ;
        RECT 4.400 323.320 854.455 324.720 ;
        RECT 4.000 317.920 854.455 323.320 ;
        RECT 4.000 316.560 854.055 317.920 ;
        RECT 4.400 316.520 854.055 316.560 ;
        RECT 4.400 315.160 854.455 316.520 ;
        RECT 4.000 308.400 854.455 315.160 ;
        RECT 4.400 307.000 854.455 308.400 ;
        RECT 4.000 305.680 854.455 307.000 ;
        RECT 4.000 304.280 854.055 305.680 ;
        RECT 4.000 300.240 854.455 304.280 ;
        RECT 4.400 298.840 854.455 300.240 ;
        RECT 4.000 293.440 854.455 298.840 ;
        RECT 4.000 292.080 854.055 293.440 ;
        RECT 4.400 292.040 854.055 292.080 ;
        RECT 4.400 290.680 854.455 292.040 ;
        RECT 4.000 283.920 854.455 290.680 ;
        RECT 4.400 282.520 854.455 283.920 ;
        RECT 4.000 281.200 854.455 282.520 ;
        RECT 4.000 279.800 854.055 281.200 ;
        RECT 4.000 275.760 854.455 279.800 ;
        RECT 4.400 274.360 854.455 275.760 ;
        RECT 4.000 268.960 854.455 274.360 ;
        RECT 4.000 267.600 854.055 268.960 ;
        RECT 4.400 267.560 854.055 267.600 ;
        RECT 4.400 266.200 854.455 267.560 ;
        RECT 4.000 259.440 854.455 266.200 ;
        RECT 4.400 258.040 854.455 259.440 ;
        RECT 4.000 256.720 854.455 258.040 ;
        RECT 4.000 255.320 854.055 256.720 ;
        RECT 4.000 251.280 854.455 255.320 ;
        RECT 4.400 249.880 854.455 251.280 ;
        RECT 4.000 244.480 854.455 249.880 ;
        RECT 4.000 243.120 854.055 244.480 ;
        RECT 4.400 243.080 854.055 243.120 ;
        RECT 4.400 241.720 854.455 243.080 ;
        RECT 4.000 234.960 854.455 241.720 ;
        RECT 4.400 233.560 854.455 234.960 ;
        RECT 4.000 232.240 854.455 233.560 ;
        RECT 4.000 230.840 854.055 232.240 ;
        RECT 4.000 226.800 854.455 230.840 ;
        RECT 4.400 225.400 854.455 226.800 ;
        RECT 4.000 220.000 854.455 225.400 ;
        RECT 4.000 218.640 854.055 220.000 ;
        RECT 4.400 218.600 854.055 218.640 ;
        RECT 4.400 217.240 854.455 218.600 ;
        RECT 4.000 210.480 854.455 217.240 ;
        RECT 4.400 209.080 854.455 210.480 ;
        RECT 4.000 207.760 854.455 209.080 ;
        RECT 4.000 206.360 854.055 207.760 ;
        RECT 4.000 202.320 854.455 206.360 ;
        RECT 4.400 200.920 854.455 202.320 ;
        RECT 4.000 195.520 854.455 200.920 ;
        RECT 4.000 194.160 854.055 195.520 ;
        RECT 4.400 194.120 854.055 194.160 ;
        RECT 4.400 192.760 854.455 194.120 ;
        RECT 4.000 186.000 854.455 192.760 ;
        RECT 4.400 184.600 854.455 186.000 ;
        RECT 4.000 183.280 854.455 184.600 ;
        RECT 4.000 181.880 854.055 183.280 ;
        RECT 4.000 177.840 854.455 181.880 ;
        RECT 4.400 176.440 854.455 177.840 ;
        RECT 4.000 171.040 854.455 176.440 ;
        RECT 4.000 169.680 854.055 171.040 ;
        RECT 4.400 169.640 854.055 169.680 ;
        RECT 4.400 168.280 854.455 169.640 ;
        RECT 4.000 161.520 854.455 168.280 ;
        RECT 4.400 160.120 854.455 161.520 ;
        RECT 4.000 158.800 854.455 160.120 ;
        RECT 4.000 157.400 854.055 158.800 ;
        RECT 4.000 153.360 854.455 157.400 ;
        RECT 4.400 151.960 854.455 153.360 ;
        RECT 4.000 146.560 854.455 151.960 ;
        RECT 4.000 145.200 854.055 146.560 ;
        RECT 4.400 145.160 854.055 145.200 ;
        RECT 4.400 143.800 854.455 145.160 ;
        RECT 4.000 137.040 854.455 143.800 ;
        RECT 4.400 135.640 854.455 137.040 ;
        RECT 4.000 134.320 854.455 135.640 ;
        RECT 4.000 132.920 854.055 134.320 ;
        RECT 4.000 128.880 854.455 132.920 ;
        RECT 4.400 127.480 854.455 128.880 ;
        RECT 4.000 122.080 854.455 127.480 ;
        RECT 4.000 120.720 854.055 122.080 ;
        RECT 4.400 120.680 854.055 120.720 ;
        RECT 4.400 119.320 854.455 120.680 ;
        RECT 4.000 112.560 854.455 119.320 ;
        RECT 4.400 111.160 854.455 112.560 ;
        RECT 4.000 109.840 854.455 111.160 ;
        RECT 4.000 108.440 854.055 109.840 ;
        RECT 4.000 104.400 854.455 108.440 ;
        RECT 4.400 103.000 854.455 104.400 ;
        RECT 4.000 97.600 854.455 103.000 ;
        RECT 4.000 96.240 854.055 97.600 ;
        RECT 4.400 96.200 854.055 96.240 ;
        RECT 4.400 94.840 854.455 96.200 ;
        RECT 4.000 88.080 854.455 94.840 ;
        RECT 4.400 86.680 854.455 88.080 ;
        RECT 4.000 85.360 854.455 86.680 ;
        RECT 4.000 83.960 854.055 85.360 ;
        RECT 4.000 79.920 854.455 83.960 ;
        RECT 4.400 78.520 854.455 79.920 ;
        RECT 4.000 73.120 854.455 78.520 ;
        RECT 4.000 71.760 854.055 73.120 ;
        RECT 4.400 71.720 854.055 71.760 ;
        RECT 4.400 70.360 854.455 71.720 ;
        RECT 4.000 63.600 854.455 70.360 ;
        RECT 4.400 62.200 854.455 63.600 ;
        RECT 4.000 60.880 854.455 62.200 ;
        RECT 4.000 59.480 854.055 60.880 ;
        RECT 4.000 55.440 854.455 59.480 ;
        RECT 4.400 54.040 854.455 55.440 ;
        RECT 4.000 48.640 854.455 54.040 ;
        RECT 4.000 47.280 854.055 48.640 ;
        RECT 4.400 47.240 854.055 47.280 ;
        RECT 4.400 45.880 854.455 47.240 ;
        RECT 4.000 39.120 854.455 45.880 ;
        RECT 4.400 37.720 854.455 39.120 ;
        RECT 4.000 36.400 854.455 37.720 ;
        RECT 4.000 35.000 854.055 36.400 ;
        RECT 4.000 30.960 854.455 35.000 ;
        RECT 4.400 29.560 854.455 30.960 ;
        RECT 4.000 24.160 854.455 29.560 ;
        RECT 4.000 22.800 854.055 24.160 ;
        RECT 4.400 22.760 854.055 22.800 ;
        RECT 4.400 21.400 854.455 22.760 ;
        RECT 4.000 14.640 854.455 21.400 ;
        RECT 4.400 13.240 854.455 14.640 ;
        RECT 4.000 11.920 854.455 13.240 ;
        RECT 4.000 10.520 854.055 11.920 ;
        RECT 4.000 6.480 854.455 10.520 ;
        RECT 4.400 5.615 854.455 6.480 ;
      LAYER met4 ;
        RECT 18.695 10.240 20.640 852.545 ;
        RECT 23.040 10.240 110.640 852.545 ;
        RECT 113.040 10.240 200.640 852.545 ;
        RECT 203.040 10.240 290.640 852.545 ;
        RECT 293.040 10.240 380.640 852.545 ;
        RECT 383.040 10.240 470.640 852.545 ;
        RECT 473.040 10.240 560.640 852.545 ;
        RECT 563.040 10.240 650.640 852.545 ;
        RECT 653.040 10.240 740.640 852.545 ;
        RECT 743.040 10.240 771.585 852.545 ;
        RECT 18.695 9.015 771.585 10.240 ;
      LAYER met5 ;
        RECT 233.340 266.100 442.860 274.500 ;
  END
END peripheral_unit
END LIBRARY

